##
## LEF for PtnCells ;
## created by Innovus v17.13-s098_1 on Sat Dec 14 20:47:54 2019
##

VERSION 5.8 ;

BUSBITCHARS "[]" ;
DIVIDERCHAR "/" ;

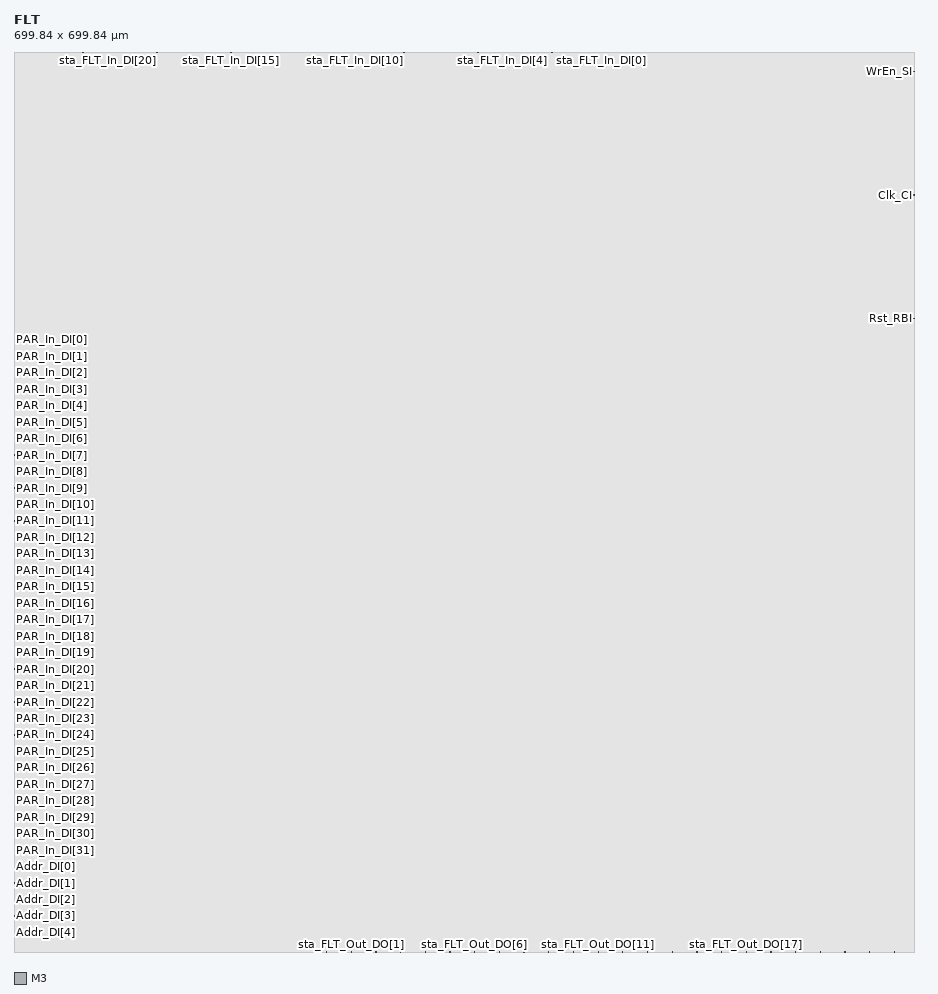
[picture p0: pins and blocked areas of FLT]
MACRO FLT
  CLASS BLOCK ;
  SIZE 699.8400 BY 699.8400 ;
  FOREIGN FLT 0.0000 0.0000 ;
  ORIGIN 0 0 ;
  SYMMETRY X Y R90 ;
  PIN Clk_CI
    DIRECTION INPUT ;
    USE SIGNAL ;
    PORT
      LAYER M3 ;
        RECT 699.6800 588.5600 699.8400 588.7200 ;
    END
  END Clk_CI
  PIN Rst_RBI
    DIRECTION INPUT ;
    USE SIGNAL ;
    PORT
      LAYER M3 ;
        RECT 699.6800 492.5600 699.8400 492.7200 ;
    END
  END Rst_RBI
  PIN WrEn_SI
    DIRECTION INPUT ;
    USE SIGNAL ;
    PORT
      LAYER M3 ;
        RECT 699.6800 684.5600 699.8400 684.7200 ;
    END
  END WrEn_SI
  PIN Addr_DI[4]
    DIRECTION INPUT ;
    USE SIGNAL ;
    PORT
      LAYER M3 ;
        RECT 0.0000 15.1200 0.1600 15.2800 ;
    END
  END Addr_DI[4]
  PIN Addr_DI[3]
    DIRECTION INPUT ;
    USE SIGNAL ;
    PORT
      LAYER M3 ;
        RECT 0.0000 27.9200 0.1600 28.0800 ;
    END
  END Addr_DI[3]
  PIN Addr_DI[2]
    DIRECTION INPUT ;
    USE SIGNAL ;
    PORT
      LAYER M3 ;
        RECT 0.0000 40.7200 0.1600 40.8800 ;
    END
  END Addr_DI[2]
  PIN Addr_DI[1]
    DIRECTION INPUT ;
    USE SIGNAL ;
    PORT
      LAYER M3 ;
        RECT 0.0000 53.5200 0.1600 53.6800 ;
    END
  END Addr_DI[1]
  PIN Addr_DI[0]
    DIRECTION INPUT ;
    USE SIGNAL ;
    PORT
      LAYER M3 ;
        RECT 0.0000 66.3200 0.1600 66.4800 ;
    END
  END Addr_DI[0]
  PIN PAR_In_DI[31]
    DIRECTION INPUT ;
    USE SIGNAL ;
    PORT
      LAYER M3 ;
        RECT 0.0000 79.1200 0.1600 79.2800 ;
    END
  END PAR_In_DI[31]
  PIN PAR_In_DI[30]
    DIRECTION INPUT ;
    USE SIGNAL ;
    PORT
      LAYER M3 ;
        RECT 0.0000 91.9200 0.1600 92.0800 ;
    END
  END PAR_In_DI[30]
  PIN PAR_In_DI[29]
    DIRECTION INPUT ;
    USE SIGNAL ;
    PORT
      LAYER M3 ;
        RECT 0.0000 104.7200 0.1600 104.8800 ;
    END
  END PAR_In_DI[29]
  PIN PAR_In_DI[28]
    DIRECTION INPUT ;
    USE SIGNAL ;
    PORT
      LAYER M3 ;
        RECT 0.0000 117.5200 0.1600 117.6800 ;
    END
  END PAR_In_DI[28]
  PIN PAR_In_DI[27]
    DIRECTION INPUT ;
    USE SIGNAL ;
    PORT
      LAYER M3 ;
        RECT 0.0000 130.3200 0.1600 130.4800 ;
    END
  END PAR_In_DI[27]
  PIN PAR_In_DI[26]
    DIRECTION INPUT ;
    USE SIGNAL ;
    PORT
      LAYER M3 ;
        RECT 0.0000 143.1200 0.1600 143.2800 ;
    END
  END PAR_In_DI[26]
  PIN PAR_In_DI[25]
    DIRECTION INPUT ;
    USE SIGNAL ;
    PORT
      LAYER M3 ;
        RECT 0.0000 155.9200 0.1600 156.0800 ;
    END
  END PAR_In_DI[25]
  PIN PAR_In_DI[24]
    DIRECTION INPUT ;
    USE SIGNAL ;
    PORT
      LAYER M3 ;
        RECT 0.0000 168.7200 0.1600 168.8800 ;
    END
  END PAR_In_DI[24]
  PIN PAR_In_DI[23]
    DIRECTION INPUT ;
    USE SIGNAL ;
    PORT
      LAYER M3 ;
        RECT 0.0000 181.5200 0.1600 181.6800 ;
    END
  END PAR_In_DI[23]
  PIN PAR_In_DI[22]
    DIRECTION INPUT ;
    USE SIGNAL ;
    PORT
      LAYER M3 ;
        RECT 0.0000 194.3200 0.1600 194.4800 ;
    END
  END PAR_In_DI[22]
  PIN PAR_In_DI[21]
    DIRECTION INPUT ;
    USE SIGNAL ;
    PORT
      LAYER M3 ;
        RECT 0.0000 207.1200 0.1600 207.2800 ;
    END
  END PAR_In_DI[21]
  PIN PAR_In_DI[20]
    DIRECTION INPUT ;
    USE SIGNAL ;
    PORT
      LAYER M3 ;
        RECT 0.0000 219.9200 0.1600 220.0800 ;
    END
  END PAR_In_DI[20]
  PIN PAR_In_DI[19]
    DIRECTION INPUT ;
    USE SIGNAL ;
    PORT
      LAYER M3 ;
        RECT 0.0000 232.7200 0.1600 232.8800 ;
    END
  END PAR_In_DI[19]
  PIN PAR_In_DI[18]
    DIRECTION INPUT ;
    USE SIGNAL ;
    PORT
      LAYER M3 ;
        RECT 0.0000 245.5200 0.1600 245.6800 ;
    END
  END PAR_In_DI[18]
  PIN PAR_In_DI[17]
    DIRECTION INPUT ;
    USE SIGNAL ;
    PORT
      LAYER M3 ;
        RECT 0.0000 258.3200 0.1600 258.4800 ;
    END
  END PAR_In_DI[17]
  PIN PAR_In_DI[16]
    DIRECTION INPUT ;
    USE SIGNAL ;
    PORT
      LAYER M3 ;
        RECT 0.0000 271.1200 0.1600 271.2800 ;
    END
  END PAR_In_DI[16]
  PIN PAR_In_DI[15]
    DIRECTION INPUT ;
    USE SIGNAL ;
    PORT
      LAYER M3 ;
        RECT 0.0000 283.9200 0.1600 284.0800 ;
    END
  END PAR_In_DI[15]
  PIN PAR_In_DI[14]
    DIRECTION INPUT ;
    USE SIGNAL ;
    PORT
      LAYER M3 ;
        RECT 0.0000 296.7200 0.1600 296.8800 ;
    END
  END PAR_In_DI[14]
  PIN PAR_In_DI[13]
    DIRECTION INPUT ;
    USE SIGNAL ;
    PORT
      LAYER M3 ;
        RECT 0.0000 309.5200 0.1600 309.6800 ;
    END
  END PAR_In_DI[13]
  PIN PAR_In_DI[12]
    DIRECTION INPUT ;
    USE SIGNAL ;
    PORT
      LAYER M3 ;
        RECT 0.0000 322.3200 0.1600 322.4800 ;
    END
  END PAR_In_DI[12]
  PIN PAR_In_DI[11]
    DIRECTION INPUT ;
    USE SIGNAL ;
    PORT
      LAYER M3 ;
        RECT 0.0000 335.1200 0.1600 335.2800 ;
    END
  END PAR_In_DI[11]
  PIN PAR_In_DI[10]
    DIRECTION INPUT ;
    USE SIGNAL ;
    PORT
      LAYER M3 ;
        RECT 0.0000 347.9200 0.1600 348.0800 ;
    END
  END PAR_In_DI[10]
  PIN PAR_In_DI[9]
    DIRECTION INPUT ;
    USE SIGNAL ;
    PORT
      LAYER M3 ;
        RECT 0.0000 360.7200 0.1600 360.8800 ;
    END
  END PAR_In_DI[9]
  PIN PAR_In_DI[8]
    DIRECTION INPUT ;
    USE SIGNAL ;
    PORT
      LAYER M3 ;
        RECT 0.0000 373.5200 0.1600 373.6800 ;
    END
  END PAR_In_DI[8]
  PIN PAR_In_DI[7]
    DIRECTION INPUT ;
    USE SIGNAL ;
    PORT
      LAYER M3 ;
        RECT 0.0000 386.3200 0.1600 386.4800 ;
    END
  END PAR_In_DI[7]
  PIN PAR_In_DI[6]
    DIRECTION INPUT ;
    USE SIGNAL ;
    PORT
      LAYER M3 ;
        RECT 0.0000 399.1200 0.1600 399.2800 ;
    END
  END PAR_In_DI[6]
  PIN PAR_In_DI[5]
    DIRECTION INPUT ;
    USE SIGNAL ;
    PORT
      LAYER M3 ;
        RECT 0.0000 411.9200 0.1600 412.0800 ;
    END
  END PAR_In_DI[5]
  PIN PAR_In_DI[4]
    DIRECTION INPUT ;
    USE SIGNAL ;
    PORT
      LAYER M3 ;
        RECT 0.0000 424.7200 0.1600 424.8800 ;
    END
  END PAR_In_DI[4]
  PIN PAR_In_DI[3]
    DIRECTION INPUT ;
    USE SIGNAL ;
    PORT
      LAYER M3 ;
        RECT 0.0000 437.5200 0.1600 437.6800 ;
    END
  END PAR_In_DI[3]
  PIN PAR_In_DI[2]
    DIRECTION INPUT ;
    USE SIGNAL ;
    PORT
      LAYER M3 ;
        RECT 0.0000 450.3200 0.1600 450.4800 ;
    END
  END PAR_In_DI[2]
  PIN PAR_In_DI[1]
    DIRECTION INPUT ;
    USE SIGNAL ;
    PORT
      LAYER M3 ;
        RECT 0.0000 463.1200 0.1600 463.2800 ;
    END
  END PAR_In_DI[1]
  PIN PAR_In_DI[0]
    DIRECTION INPUT ;
    USE SIGNAL ;
    PORT
      LAYER M3 ;
        RECT 0.0000 475.9200 0.1600 476.0800 ;
    END
  END PAR_In_DI[0]
  PIN sta_FLT_In_DI[23]
    DIRECTION INPUT ;
    USE SIGNAL ;
    PORT
      LAYER M3 ;
        RECT 15.1200 699.6800 15.2800 699.8400 ;
    END
  END sta_FLT_In_DI[23]
  PIN sta_FLT_In_DI[22]
    DIRECTION INPUT ;
    USE SIGNAL ;
    PORT
      LAYER M3 ;
        RECT 34.3200 699.6800 34.4800 699.8400 ;
    END
  END sta_FLT_In_DI[22]
  PIN sta_FLT_In_DI[21]
    DIRECTION INPUT ;
    USE SIGNAL ;
    PORT
      LAYER M3 ;
        RECT 53.5200 699.6800 53.6800 699.8400 ;
    END
  END sta_FLT_In_DI[21]
  PIN sta_FLT_In_DI[20]
    DIRECTION INPUT ;
    USE SIGNAL ;
    PORT
      LAYER M3 ;
        RECT 72.7200 699.6800 72.8800 699.8400 ;
    END
  END sta_FLT_In_DI[20]
  PIN sta_FLT_In_DI[19]
    DIRECTION INPUT ;
    USE SIGNAL ;
    PORT
      LAYER M3 ;
        RECT 91.9200 699.6800 92.0800 699.8400 ;
    END
  END sta_FLT_In_DI[19]
  PIN sta_FLT_In_DI[18]
    DIRECTION INPUT ;
    USE SIGNAL ;
    PORT
      LAYER M3 ;
        RECT 111.1200 699.6800 111.2800 699.8400 ;
    END
  END sta_FLT_In_DI[18]
  PIN sta_FLT_In_DI[17]
    DIRECTION INPUT ;
    USE SIGNAL ;
    PORT
      LAYER M3 ;
        RECT 130.3200 699.6800 130.4800 699.8400 ;
    END
  END sta_FLT_In_DI[17]
  PIN sta_FLT_In_DI[16]
    DIRECTION INPUT ;
    USE SIGNAL ;
    PORT
      LAYER M3 ;
        RECT 149.5200 699.6800 149.6800 699.8400 ;
    END
  END sta_FLT_In_DI[16]
  PIN sta_FLT_In_DI[15]
    DIRECTION INPUT ;
    USE SIGNAL ;
    PORT
      LAYER M3 ;
        RECT 168.7200 699.6800 168.8800 699.8400 ;
    END
  END sta_FLT_In_DI[15]
  PIN sta_FLT_In_DI[14]
    DIRECTION INPUT ;
    USE SIGNAL ;
    PORT
      LAYER M3 ;
        RECT 187.9200 699.6800 188.0800 699.8400 ;
    END
  END sta_FLT_In_DI[14]
  PIN sta_FLT_In_DI[13]
    DIRECTION INPUT ;
    USE SIGNAL ;
    PORT
      LAYER M3 ;
        RECT 207.1200 699.6800 207.2800 699.8400 ;
    END
  END sta_FLT_In_DI[13]
  PIN sta_FLT_In_DI[12]
    DIRECTION INPUT ;
    USE SIGNAL ;
    PORT
      LAYER M3 ;
        RECT 226.3200 699.6800 226.4800 699.8400 ;
    END
  END sta_FLT_In_DI[12]
  PIN sta_FLT_In_DI[11]
    DIRECTION INPUT ;
    USE SIGNAL ;
    PORT
      LAYER M3 ;
        RECT 245.5200 699.6800 245.6800 699.8400 ;
    END
  END sta_FLT_In_DI[11]
  PIN sta_FLT_In_DI[10]
    DIRECTION INPUT ;
    USE SIGNAL ;
    PORT
      LAYER M3 ;
        RECT 264.7200 699.6800 264.8800 699.8400 ;
    END
  END sta_FLT_In_DI[10]
  PIN sta_FLT_In_DI[9]
    DIRECTION INPUT ;
    USE SIGNAL ;
    PORT
      LAYER M3 ;
        RECT 283.9200 699.6800 284.0800 699.8400 ;
    END
  END sta_FLT_In_DI[9]
  PIN sta_FLT_In_DI[8]
    DIRECTION INPUT ;
    USE SIGNAL ;
    PORT
      LAYER M3 ;
        RECT 303.1200 699.6800 303.2800 699.8400 ;
    END
  END sta_FLT_In_DI[8]
  PIN sta_FLT_In_DI[7]
    DIRECTION INPUT ;
    USE SIGNAL ;
    PORT
      LAYER M3 ;
        RECT 322.3200 699.6800 322.4800 699.8400 ;
    END
  END sta_FLT_In_DI[7]
  PIN sta_FLT_In_DI[6]
    DIRECTION INPUT ;
    USE SIGNAL ;
    PORT
      LAYER M3 ;
        RECT 341.5200 699.6800 341.6800 699.8400 ;
    END
  END sta_FLT_In_DI[6]
  PIN sta_FLT_In_DI[5]
    DIRECTION INPUT ;
    USE SIGNAL ;
    PORT
      LAYER M3 ;
        RECT 360.7200 699.6800 360.8800 699.8400 ;
    END
  END sta_FLT_In_DI[5]
  PIN sta_FLT_In_DI[4]
    DIRECTION INPUT ;
    USE SIGNAL ;
    PORT
      LAYER M3 ;
        RECT 379.9200 699.6800 380.0800 699.8400 ;
    END
  END sta_FLT_In_DI[4]
  PIN sta_FLT_In_DI[3]
    DIRECTION INPUT ;
    USE SIGNAL ;
    PORT
      LAYER M3 ;
        RECT 399.1200 699.6800 399.2800 699.8400 ;
    END
  END sta_FLT_In_DI[3]
  PIN sta_FLT_In_DI[2]
    DIRECTION INPUT ;
    USE SIGNAL ;
    PORT
      LAYER M3 ;
        RECT 418.3200 699.6800 418.4800 699.8400 ;
    END
  END sta_FLT_In_DI[2]
  PIN sta_FLT_In_DI[1]
    DIRECTION INPUT ;
    USE SIGNAL ;
    PORT
      LAYER M3 ;
        RECT 437.5200 699.6800 437.6800 699.8400 ;
    END
  END sta_FLT_In_DI[1]
  PIN sta_FLT_In_DI[0]
    DIRECTION INPUT ;
    USE SIGNAL ;
    PORT
      LAYER M3 ;
        RECT 456.7200 699.6800 456.8800 699.8400 ;
    END
  END sta_FLT_In_DI[0]
  PIN sta_FLT_Out_DO[23]
    DIRECTION OUTPUT ;
    USE SIGNAL ;
    PORT
      LAYER M3 ;
        RECT 684.5600 0.0000 684.7200 0.1600 ;
    END
  END sta_FLT_Out_DO[23]
  PIN sta_FLT_Out_DO[22]
    DIRECTION OUTPUT ;
    USE SIGNAL ;
    PORT
      LAYER M3 ;
        RECT 665.3600 0.0000 665.5200 0.1600 ;
    END
  END sta_FLT_Out_DO[22]
  PIN sta_FLT_Out_DO[21]
    DIRECTION OUTPUT ;
    USE SIGNAL ;
    PORT
      LAYER M3 ;
        RECT 646.1600 0.0000 646.3200 0.1600 ;
    END
  END sta_FLT_Out_DO[21]
  PIN sta_FLT_Out_DO[20]
    DIRECTION OUTPUT ;
    USE SIGNAL ;
    PORT
      LAYER M3 ;
        RECT 626.9600 0.0000 627.1200 0.1600 ;
    END
  END sta_FLT_Out_DO[20]
  PIN sta_FLT_Out_DO[19]
    DIRECTION OUTPUT ;
    USE SIGNAL ;
    PORT
      LAYER M3 ;
        RECT 607.7600 0.0000 607.9200 0.1600 ;
    END
  END sta_FLT_Out_DO[19]
  PIN sta_FLT_Out_DO[18]
    DIRECTION OUTPUT ;
    USE SIGNAL ;
    PORT
      LAYER M3 ;
        RECT 588.5600 0.0000 588.7200 0.1600 ;
    END
  END sta_FLT_Out_DO[18]
  PIN sta_FLT_Out_DO[17]
    DIRECTION OUTPUT ;
    USE SIGNAL ;
    PORT
      LAYER M3 ;
        RECT 569.3600 0.0000 569.5200 0.1600 ;
    END
  END sta_FLT_Out_DO[17]
  PIN sta_FLT_Out_DO[16]
    DIRECTION OUTPUT ;
    USE SIGNAL ;
    PORT
      LAYER M3 ;
        RECT 550.1600 0.0000 550.3200 0.1600 ;
    END
  END sta_FLT_Out_DO[16]
  PIN sta_FLT_Out_DO[15]
    DIRECTION OUTPUT ;
    USE SIGNAL ;
    PORT
      LAYER M3 ;
        RECT 530.9600 0.0000 531.1200 0.1600 ;
    END
  END sta_FLT_Out_DO[15]
  PIN sta_FLT_Out_DO[14]
    DIRECTION OUTPUT ;
    USE SIGNAL ;
    PORT
      LAYER M3 ;
        RECT 511.7600 0.0000 511.9200 0.1600 ;
    END
  END sta_FLT_Out_DO[14]
  PIN sta_FLT_Out_DO[13]
    DIRECTION OUTPUT ;
    USE SIGNAL ;
    PORT
      LAYER M3 ;
        RECT 492.5600 0.0000 492.7200 0.1600 ;
    END
  END sta_FLT_Out_DO[13]
  PIN sta_FLT_Out_DO[12]
    DIRECTION OUTPUT ;
    USE SIGNAL ;
    PORT
      LAYER M3 ;
        RECT 473.3600 0.0000 473.5200 0.1600 ;
    END
  END sta_FLT_Out_DO[12]
  PIN sta_FLT_Out_DO[11]
    DIRECTION OUTPUT ;
    USE SIGNAL ;
    PORT
      LAYER M3 ;
        RECT 454.1600 0.0000 454.3200 0.1600 ;
    END
  END sta_FLT_Out_DO[11]
  PIN sta_FLT_Out_DO[10]
    DIRECTION OUTPUT ;
    USE SIGNAL ;
    PORT
      LAYER M3 ;
        RECT 434.9600 0.0000 435.1200 0.1600 ;
    END
  END sta_FLT_Out_DO[10]
  PIN sta_FLT_Out_DO[9]
    DIRECTION OUTPUT ;
    USE SIGNAL ;
    PORT
      LAYER M3 ;
        RECT 415.7600 0.0000 415.9200 0.1600 ;
    END
  END sta_FLT_Out_DO[9]
  PIN sta_FLT_Out_DO[8]
    DIRECTION OUTPUT ;
    USE SIGNAL ;
    PORT
      LAYER M3 ;
        RECT 396.5600 0.0000 396.7200 0.1600 ;
    END
  END sta_FLT_Out_DO[8]
  PIN sta_FLT_Out_DO[7]
    DIRECTION OUTPUT ;
    USE SIGNAL ;
    PORT
      LAYER M3 ;
        RECT 377.3600 0.0000 377.5200 0.1600 ;
    END
  END sta_FLT_Out_DO[7]
  PIN sta_FLT_Out_DO[6]
    DIRECTION OUTPUT ;
    USE SIGNAL ;
    PORT
      LAYER M3 ;
        RECT 358.1600 0.0000 358.3200 0.1600 ;
    END
  END sta_FLT_Out_DO[6]
  PIN sta_FLT_Out_DO[5]
    DIRECTION OUTPUT ;
    USE SIGNAL ;
    PORT
      LAYER M3 ;
        RECT 338.9600 0.0000 339.1200 0.1600 ;
    END
  END sta_FLT_Out_DO[5]
  PIN sta_FLT_Out_DO[4]
    DIRECTION OUTPUT ;
    USE SIGNAL ;
    PORT
      LAYER M3 ;
        RECT 319.7600 0.0000 319.9200 0.1600 ;
    END
  END sta_FLT_Out_DO[4]
  PIN sta_FLT_Out_DO[3]
    DIRECTION OUTPUT ;
    USE SIGNAL ;
    PORT
      LAYER M3 ;
        RECT 300.5600 0.0000 300.7200 0.1600 ;
    END
  END sta_FLT_Out_DO[3]
  PIN sta_FLT_Out_DO[2]
    DIRECTION OUTPUT ;
    USE SIGNAL ;
    PORT
      LAYER M3 ;
        RECT 281.3600 0.0000 281.5200 0.1600 ;
    END
  END sta_FLT_Out_DO[2]
  PIN sta_FLT_Out_DO[1]
    DIRECTION OUTPUT ;
    USE SIGNAL ;
    PORT
      LAYER M3 ;
        RECT 262.1600 0.0000 262.3200 0.1600 ;
    END
  END sta_FLT_Out_DO[1]
  PIN sta_FLT_Out_DO[0]
    DIRECTION OUTPUT ;
    USE SIGNAL ;
    PORT
      LAYER M3 ;
        RECT 242.9600 0.0000 243.1200 0.1600 ;
    END
  END sta_FLT_Out_DO[0]
  OBS
    LAYER M1 ;
      RECT 0.0000 0.0000 699.8400 699.8400 ;
    LAYER M2 ;
      RECT 0.0000 0.0000 699.8400 699.8400 ;
    LAYER M3 ;
      RECT 457.0400 699.5200 699.8400 699.8400 ;
      RECT 437.8400 699.5200 456.5600 699.8400 ;
      RECT 418.6400 699.5200 437.3600 699.8400 ;
      RECT 399.4400 699.5200 418.1600 699.8400 ;
      RECT 380.2400 699.5200 398.9600 699.8400 ;
      RECT 361.0400 699.5200 379.7600 699.8400 ;
      RECT 341.8400 699.5200 360.5600 699.8400 ;
      RECT 322.6400 699.5200 341.3600 699.8400 ;
      RECT 303.4400 699.5200 322.1600 699.8400 ;
      RECT 284.2400 699.5200 302.9600 699.8400 ;
      RECT 265.0400 699.5200 283.7600 699.8400 ;
      RECT 245.8400 699.5200 264.5600 699.8400 ;
      RECT 226.6400 699.5200 245.3600 699.8400 ;
      RECT 207.4400 699.5200 226.1600 699.8400 ;
      RECT 188.2400 699.5200 206.9600 699.8400 ;
      RECT 169.0400 699.5200 187.7600 699.8400 ;
      RECT 149.8400 699.5200 168.5600 699.8400 ;
      RECT 130.6400 699.5200 149.3600 699.8400 ;
      RECT 111.4400 699.5200 130.1600 699.8400 ;
      RECT 92.2400 699.5200 110.9600 699.8400 ;
      RECT 73.0400 699.5200 91.7600 699.8400 ;
      RECT 53.8400 699.5200 72.5600 699.8400 ;
      RECT 34.6400 699.5200 53.3600 699.8400 ;
      RECT 15.4400 699.5200 34.1600 699.8400 ;
      RECT 0.0000 699.5200 14.9600 699.8400 ;
      RECT 0.0000 684.8800 699.8400 699.5200 ;
      RECT 0.0000 684.4000 699.5200 684.8800 ;
      RECT 0.0000 588.8800 699.8400 684.4000 ;
      RECT 0.0000 588.4000 699.5200 588.8800 ;
      RECT 0.0000 492.8800 699.8400 588.4000 ;
      RECT 0.0000 492.4000 699.5200 492.8800 ;
      RECT 0.0000 476.2400 699.8400 492.4000 ;
      RECT 0.3200 475.7600 699.8400 476.2400 ;
      RECT 0.0000 463.4400 699.8400 475.7600 ;
      RECT 0.3200 462.9600 699.8400 463.4400 ;
      RECT 0.0000 450.6400 699.8400 462.9600 ;
      RECT 0.3200 450.1600 699.8400 450.6400 ;
      RECT 0.0000 437.8400 699.8400 450.1600 ;
      RECT 0.3200 437.3600 699.8400 437.8400 ;
      RECT 0.0000 425.0400 699.8400 437.3600 ;
      RECT 0.3200 424.5600 699.8400 425.0400 ;
      RECT 0.0000 412.2400 699.8400 424.5600 ;
      RECT 0.3200 411.7600 699.8400 412.2400 ;
      RECT 0.0000 399.4400 699.8400 411.7600 ;
      RECT 0.3200 398.9600 699.8400 399.4400 ;
      RECT 0.0000 386.6400 699.8400 398.9600 ;
      RECT 0.3200 386.1600 699.8400 386.6400 ;
      RECT 0.0000 373.8400 699.8400 386.1600 ;
      RECT 0.3200 373.3600 699.8400 373.8400 ;
      RECT 0.0000 361.0400 699.8400 373.3600 ;
      RECT 0.3200 360.5600 699.8400 361.0400 ;
      RECT 0.0000 348.2400 699.8400 360.5600 ;
      RECT 0.3200 347.7600 699.8400 348.2400 ;
      RECT 0.0000 335.4400 699.8400 347.7600 ;
      RECT 0.3200 334.9600 699.8400 335.4400 ;
      RECT 0.0000 322.6400 699.8400 334.9600 ;
      RECT 0.3200 322.1600 699.8400 322.6400 ;
      RECT 0.0000 309.8400 699.8400 322.1600 ;
      RECT 0.3200 309.3600 699.8400 309.8400 ;
      RECT 0.0000 297.0400 699.8400 309.3600 ;
      RECT 0.3200 296.5600 699.8400 297.0400 ;
      RECT 0.0000 284.2400 699.8400 296.5600 ;
      RECT 0.3200 283.7600 699.8400 284.2400 ;
      RECT 0.0000 271.4400 699.8400 283.7600 ;
      RECT 0.3200 270.9600 699.8400 271.4400 ;
      RECT 0.0000 258.6400 699.8400 270.9600 ;
      RECT 0.3200 258.1600 699.8400 258.6400 ;
      RECT 0.0000 245.8400 699.8400 258.1600 ;
      RECT 0.3200 245.3600 699.8400 245.8400 ;
      RECT 0.0000 233.0400 699.8400 245.3600 ;
      RECT 0.3200 232.5600 699.8400 233.0400 ;
      RECT 0.0000 220.2400 699.8400 232.5600 ;
      RECT 0.3200 219.7600 699.8400 220.2400 ;
      RECT 0.0000 207.4400 699.8400 219.7600 ;
      RECT 0.3200 206.9600 699.8400 207.4400 ;
      RECT 0.0000 194.6400 699.8400 206.9600 ;
      RECT 0.3200 194.1600 699.8400 194.6400 ;
      RECT 0.0000 181.8400 699.8400 194.1600 ;
      RECT 0.3200 181.3600 699.8400 181.8400 ;
      RECT 0.0000 169.0400 699.8400 181.3600 ;
      RECT 0.3200 168.5600 699.8400 169.0400 ;
      RECT 0.0000 156.2400 699.8400 168.5600 ;
      RECT 0.3200 155.7600 699.8400 156.2400 ;
      RECT 0.0000 143.4400 699.8400 155.7600 ;
      RECT 0.3200 142.9600 699.8400 143.4400 ;
      RECT 0.0000 130.6400 699.8400 142.9600 ;
      RECT 0.3200 130.1600 699.8400 130.6400 ;
      RECT 0.0000 117.8400 699.8400 130.1600 ;
      RECT 0.3200 117.3600 699.8400 117.8400 ;
      RECT 0.0000 105.0400 699.8400 117.3600 ;
      RECT 0.3200 104.5600 699.8400 105.0400 ;
      RECT 0.0000 92.2400 699.8400 104.5600 ;
      RECT 0.3200 91.7600 699.8400 92.2400 ;
      RECT 0.0000 79.4400 699.8400 91.7600 ;
      RECT 0.3200 78.9600 699.8400 79.4400 ;
      RECT 0.0000 66.6400 699.8400 78.9600 ;
      RECT 0.3200 66.1600 699.8400 66.6400 ;
      RECT 0.0000 53.8400 699.8400 66.1600 ;
      RECT 0.3200 53.3600 699.8400 53.8400 ;
      RECT 0.0000 41.0400 699.8400 53.3600 ;
      RECT 0.3200 40.5600 699.8400 41.0400 ;
      RECT 0.0000 28.2400 699.8400 40.5600 ;
      RECT 0.3200 27.7600 699.8400 28.2400 ;
      RECT 0.0000 15.4400 699.8400 27.7600 ;
      RECT 0.3200 14.9600 699.8400 15.4400 ;
      RECT 0.0000 0.3200 699.8400 14.9600 ;
      RECT 684.8800 0.0000 699.8400 0.3200 ;
      RECT 665.6800 0.0000 684.4000 0.3200 ;
      RECT 646.4800 0.0000 665.2000 0.3200 ;
      RECT 627.2800 0.0000 646.0000 0.3200 ;
      RECT 608.0800 0.0000 626.8000 0.3200 ;
      RECT 588.8800 0.0000 607.6000 0.3200 ;
      RECT 569.6800 0.0000 588.4000 0.3200 ;
      RECT 550.4800 0.0000 569.2000 0.3200 ;
      RECT 531.2800 0.0000 550.0000 0.3200 ;
      RECT 512.0800 0.0000 530.8000 0.3200 ;
      RECT 492.8800 0.0000 511.6000 0.3200 ;
      RECT 473.6800 0.0000 492.4000 0.3200 ;
      RECT 454.4800 0.0000 473.2000 0.3200 ;
      RECT 435.2800 0.0000 454.0000 0.3200 ;
      RECT 416.0800 0.0000 434.8000 0.3200 ;
      RECT 396.8800 0.0000 415.6000 0.3200 ;
      RECT 377.6800 0.0000 396.4000 0.3200 ;
      RECT 358.4800 0.0000 377.2000 0.3200 ;
      RECT 339.2800 0.0000 358.0000 0.3200 ;
      RECT 320.0800 0.0000 338.8000 0.3200 ;
      RECT 300.8800 0.0000 319.6000 0.3200 ;
      RECT 281.6800 0.0000 300.4000 0.3200 ;
      RECT 262.4800 0.0000 281.2000 0.3200 ;
      RECT 243.2800 0.0000 262.0000 0.3200 ;
      RECT 0.0000 0.0000 242.8000 0.3200 ;
    LAYER M4 ;
      RECT 0.0000 0.0000 699.8400 699.8400 ;
    LAYER M5 ;
      RECT 0.0000 0.0000 699.8400 699.8400 ;
    LAYER M6 ;
      RECT 0.0000 0.0000 699.8400 699.8400 ;
    LAYER M7 ;
      RECT 0.0000 0.0000 699.8400 699.8400 ;
    LAYER M8 ;
      RECT 0.0000 0.0000 699.8400 699.8400 ;
    LAYER M9 ;
      RECT 0.0000 0.0000 699.8400 699.8400 ;
  END
END FLT

END LIBRARY
